# Pads from dummy_pads.lef drawn the way some pad libraries draw theirs.
# With one obstruction over the whole cell on every
# layer the pad draws, with the pins carved out of it.  The pins are
# unchanged.  The fillers draw nothing in dummy_pads.lef; in such a library
# they carry the padring on the same layers and are drawn the same way.
#
# Read it before dummy_pads.lef so these are the definitions used; the
# originals are then ignored as duplicates.
VERSION 5.8 ;

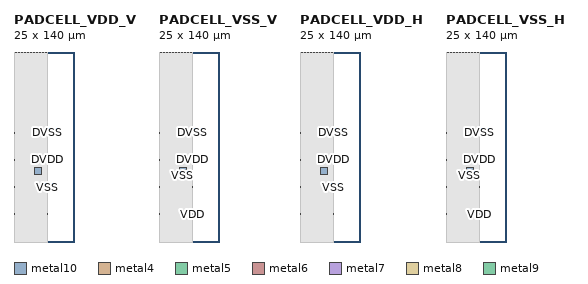
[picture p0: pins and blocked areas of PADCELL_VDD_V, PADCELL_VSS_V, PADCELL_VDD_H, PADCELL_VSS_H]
MACRO PADCELL_VDD_V
  CLASS PAD AREAIO ;
  ORIGIN 0 0 ;
  SIZE 25.0 BY 140 ;
  SYMMETRY X Y R90 ;
  PIN VDD
    DIRECTION INOUT ;
    USE POWER ;
    SHAPE ABUTMENT ;
    PORT
      CLASS BUMP ;
      LAYER metal10 ;
        RECT 15.0 50.0 20.0 55.0 ;
    END
    PORT
      CLASS CORE ;
      LAYER metal4 ;
      RECT 23.155 139.900 23.945 140.000 ;
      LAYER metal4 ;
      RECT 20.995 139.900 21.785 140.000 ;
      LAYER metal4 ;
      RECT 18.835 139.900 19.625 140.000 ;
      LAYER metal4 ;
      RECT 16.565 139.900 17.355 140.000 ;
      LAYER metal4 ;
      RECT 14.295 139.900 15.085 140.000 ;
      LAYER metal4 ;
      RECT 12.135 139.900 12.925 140.000 ;
      LAYER metal4 ;
      RECT 9.975 139.900 10.765 140.000 ;
      LAYER metal4 ;
      RECT 7.815 139.900 8.605 140.000 ;
      LAYER metal4 ;
      RECT 5.655 139.900 6.445 140.000 ;
      LAYER metal4 ;
      RECT 3.495 139.900 4.285 140.000 ;
      LAYER metal4 ;
      RECT 1.335 139.900 2.125 140.000 ;
      LAYER metal5 ;
      RECT 23.155 139.900 23.945 140.000 ;
      LAYER metal5 ;
      RECT 20.995 139.900 21.785 140.000 ;
      LAYER metal5 ;
      RECT 18.835 139.900 19.625 140.000 ;
      LAYER metal5 ;
      RECT 16.565 139.900 17.355 140.000 ;
      LAYER metal5 ;
      RECT 14.295 139.900 15.085 140.000 ;
      LAYER metal5 ;
      RECT 12.135 139.900 12.925 140.000 ;
      LAYER metal5 ;
      RECT 9.975 139.900 10.765 140.000 ;
      LAYER metal5 ;
      RECT 7.815 139.900 8.605 140.000 ;
      LAYER metal5 ;
      RECT 5.655 139.900 6.445 140.000 ;
      LAYER metal5 ;
      RECT 3.495 139.900 4.285 140.000 ;
      LAYER metal5 ;
      RECT 1.335 139.900 2.125 140.000 ;
      LAYER metal6 ;
      RECT 23.155 139.900 23.945 140.000 ;
      LAYER metal6 ;
      RECT 20.995 139.900 21.785 140.000 ;
      LAYER metal6 ;
      RECT 18.835 139.900 19.625 140.000 ;
      LAYER metal6 ;
      RECT 16.565 139.900 17.355 140.000 ;
      LAYER metal6 ;
      RECT 14.295 139.900 15.085 140.000 ;
      LAYER metal6 ;
      RECT 12.135 139.900 12.925 140.000 ;
      LAYER metal6 ;
      RECT 9.975 139.900 10.765 140.000 ;
      LAYER metal6 ;
      RECT 7.815 139.900 8.605 140.000 ;
      LAYER metal6 ;
      RECT 5.655 139.900 6.445 140.000 ;
      LAYER metal6 ;
      RECT 3.495 139.900 4.285 140.000 ;
      LAYER metal6 ;
      RECT 1.335 139.900 2.125 140.000 ;
      LAYER metal7 ;
      RECT 23.155 139.900 23.945 140.000 ;
      LAYER metal7 ;
      RECT 20.995 139.900 21.785 140.000 ;
      LAYER metal7 ;
      RECT 18.835 139.900 19.625 140.000 ;
      LAYER metal7 ;
      RECT 16.565 139.900 17.355 140.000 ;
      LAYER metal7 ;
      RECT 14.295 139.900 15.085 140.000 ;
      LAYER metal7 ;
      RECT 12.135 139.900 12.925 140.000 ;
      LAYER metal7 ;
      RECT 9.975 139.900 10.765 140.000 ;
      LAYER metal7 ;
      RECT 7.815 139.900 8.605 140.000 ;
      LAYER metal7 ;
      RECT 5.655 139.900 6.445 140.000 ;
      LAYER metal7 ;
      RECT 3.495 139.900 4.285 140.000 ;
      LAYER metal7 ;
      RECT 1.335 139.900 2.125 140.000 ;
      LAYER metal8 ;
      RECT 23.155 139.900 23.945 140.000 ;
      LAYER metal8 ;
      RECT 20.995 139.900 21.785 140.000 ;
      LAYER metal8 ;
      RECT 18.835 139.900 19.625 140.000 ;
      LAYER metal8 ;
      RECT 16.565 139.900 17.355 140.000 ;
      LAYER metal8 ;
      RECT 14.295 139.900 15.085 140.000 ;
      LAYER metal8 ;
      RECT 12.135 139.900 12.925 140.000 ;
      LAYER metal8 ;
      RECT 9.975 139.900 10.765 140.000 ;
      LAYER metal8 ;
      RECT 7.815 139.900 8.605 140.000 ;
      LAYER metal8 ;
      RECT 5.655 139.900 6.445 140.000 ;
      LAYER metal8 ;
      RECT 3.495 139.900 4.285 140.000 ;
      LAYER metal8 ;
      RECT 1.335 139.900 2.125 140.000 ;
      LAYER metal9 ;
      RECT 23.155 139.900 23.945 140.000 ;
      LAYER metal9 ;
      RECT 20.995 139.900 21.785 140.000 ;
      LAYER metal9 ;
      RECT 18.835 139.900 19.625 140.000 ;
      LAYER metal9 ;
      RECT 16.565 139.900 17.355 140.000 ;
      LAYER metal9 ;
      RECT 14.295 139.900 15.085 140.000 ;
      LAYER metal9 ;
      RECT 12.135 139.900 12.925 140.000 ;
      LAYER metal9 ;
      RECT 9.975 139.900 10.765 140.000 ;
      LAYER metal9 ;
      RECT 7.815 139.900 8.605 140.000 ;
      LAYER metal9 ;
      RECT 5.655 139.900 6.445 140.000 ;
      LAYER metal9 ;
      RECT 3.495 139.900 4.285 140.000 ;
      LAYER metal9 ;
      RECT 1.335 139.900 2.125 140.000 ;
      LAYER metal4 ;
      RECT 0.000 20.0 0.100 21.0 ;
      LAYER metal4 ;
      RECT 24.90 20.0 25.00 21.0 ;
    END
  END VDD
  PIN VSS
    USE GROUND ;
    PORT
      CLASS CORE ;
      LAYER metal4 ;
      RECT 0.000 40.0 0.100 41.0 ;
      LAYER metal4 ;
      RECT 24.90 40.0 25.00 41.0 ;
    END
  END VSS
  PIN DVDD
    USE POWER ;
    PORT
      CLASS CORE ;
      LAYER metal4 ;
      RECT 0.000 60.0 0.100 61.0 ;
      LAYER metal4 ;
      RECT 24.90 60.0 25.00 61.0 ;
    END
  END DVDD
  PIN DVSS
    USE GROUND ;
    PORT
      CLASS CORE ;
      LAYER metal4 ;
      RECT 0.000 80.0 0.100 81.0 ;
      LAYER metal4 ;
      RECT 24.90 80.0 25.00 81.0 ;
    END
  END DVSS
  OBS
    LAYER metal4 ;
      RECT 0 0 25.0 140 ;
    LAYER metal5 ;
      RECT 0 0 25.0 140 ;
    LAYER metal6 ;
      RECT 0 0 25.0 140 ;
    LAYER metal7 ;
      RECT 0 0 25.0 140 ;
    LAYER metal8 ;
      RECT 0 0 25.0 140 ;
    LAYER metal9 ;
      RECT 0 0 25.0 140 ;
    LAYER metal10 ;
      RECT 0 0 25.0 140 ;
  END
END PADCELL_VDD_V

MACRO PADCELL_VSS_V
  CLASS PAD AREAIO ;
  ORIGIN 0 0 ;
  SIZE 25.0 BY 140 ;
  SYMMETRY X Y R90 ;
  PIN VSS
    DIRECTION INOUT ;
    USE GROUND ;
    SHAPE ABUTMENT ;
    PORT
      CLASS BUMP ;
      LAYER metal10 ;
        RECT 15.0 50.0 20.0 55.0 ;
    END
    PORT
      CLASS CORE ;
      LAYER metal4 ;
      RECT 23.155 139.900 23.945 140.000 ;
      LAYER metal4 ;
      RECT 20.995 139.900 21.785 140.000 ;
      LAYER metal4 ;
      RECT 18.835 139.900 19.625 140.000 ;
      LAYER metal4 ;
      RECT 16.565 139.900 17.355 140.000 ;
      LAYER metal4 ;
      RECT 14.295 139.900 15.085 140.000 ;
      LAYER metal4 ;
      RECT 12.135 139.900 12.925 140.000 ;
      LAYER metal4 ;
      RECT 9.975 139.900 10.765 140.000 ;
      LAYER metal4 ;
      RECT 7.815 139.900 8.605 140.000 ;
      LAYER metal4 ;
      RECT 5.655 139.900 6.445 140.000 ;
      LAYER metal4 ;
      RECT 3.495 139.900 4.285 140.000 ;
      LAYER metal4 ;
      RECT 1.335 139.900 2.125 140.000 ;
      LAYER metal5 ;
      RECT 23.155 139.900 23.945 140.000 ;
      LAYER metal5 ;
      RECT 20.995 139.900 21.785 140.000 ;
      LAYER metal5 ;
      RECT 18.835 139.900 19.625 140.000 ;
      LAYER metal5 ;
      RECT 16.565 139.900 17.355 140.000 ;
      LAYER metal5 ;
      RECT 14.295 139.900 15.085 140.000 ;
      LAYER metal5 ;
      RECT 12.135 139.900 12.925 140.000 ;
      LAYER metal5 ;
      RECT 9.975 139.900 10.765 140.000 ;
      LAYER metal5 ;
      RECT 7.815 139.900 8.605 140.000 ;
      LAYER metal5 ;
      RECT 5.655 139.900 6.445 140.000 ;
      LAYER metal5 ;
      RECT 3.495 139.900 4.285 140.000 ;
      LAYER metal5 ;
      RECT 1.335 139.900 2.125 140.000 ;
      LAYER metal6 ;
      RECT 23.155 139.900 23.945 140.000 ;
      LAYER metal6 ;
      RECT 20.995 139.900 21.785 140.000 ;
      LAYER metal6 ;
      RECT 18.835 139.900 19.625 140.000 ;
      LAYER metal6 ;
      RECT 16.565 139.900 17.355 140.000 ;
      LAYER metal6 ;
      RECT 14.295 139.900 15.085 140.000 ;
      LAYER metal6 ;
      RECT 12.135 139.900 12.925 140.000 ;
      LAYER metal6 ;
      RECT 9.975 139.900 10.765 140.000 ;
      LAYER metal6 ;
      RECT 7.815 139.900 8.605 140.000 ;
      LAYER metal6 ;
      RECT 5.655 139.900 6.445 140.000 ;
      LAYER metal6 ;
      RECT 3.495 139.900 4.285 140.000 ;
      LAYER metal6 ;
      RECT 1.335 139.900 2.125 140.000 ;
      LAYER metal7 ;
      RECT 23.155 139.900 23.945 140.000 ;
      LAYER metal7 ;
      RECT 20.995 139.900 21.785 140.000 ;
      LAYER metal7 ;
      RECT 18.835 139.900 19.625 140.000 ;
      LAYER metal7 ;
      RECT 16.565 139.900 17.355 140.000 ;
      LAYER metal7 ;
      RECT 14.295 139.900 15.085 140.000 ;
      LAYER metal7 ;
      RECT 12.135 139.900 12.925 140.000 ;
      LAYER metal7 ;
      RECT 9.975 139.900 10.765 140.000 ;
      LAYER metal7 ;
      RECT 7.815 139.900 8.605 140.000 ;
      LAYER metal7 ;
      RECT 5.655 139.900 6.445 140.000 ;
      LAYER metal7 ;
      RECT 3.495 139.900 4.285 140.000 ;
      LAYER metal7 ;
      RECT 1.335 139.900 2.125 140.000 ;
      LAYER metal8 ;
      RECT 23.155 139.900 23.945 140.000 ;
      LAYER metal8 ;
      RECT 20.995 139.900 21.785 140.000 ;
      LAYER metal8 ;
      RECT 18.835 139.900 19.625 140.000 ;
      LAYER metal8 ;
      RECT 16.565 139.900 17.355 140.000 ;
      LAYER metal8 ;
      RECT 14.295 139.900 15.085 140.000 ;
      LAYER metal8 ;
      RECT 12.135 139.900 12.925 140.000 ;
      LAYER metal8 ;
      RECT 9.975 139.900 10.765 140.000 ;
      LAYER metal8 ;
      RECT 7.815 139.900 8.605 140.000 ;
      LAYER metal8 ;
      RECT 5.655 139.900 6.445 140.000 ;
      LAYER metal8 ;
      RECT 3.495 139.900 4.285 140.000 ;
      LAYER metal8 ;
      RECT 1.335 139.900 2.125 140.000 ;
      LAYER metal9 ;
      RECT 23.155 139.900 23.945 140.000 ;
      LAYER metal9 ;
      RECT 20.995 139.900 21.785 140.000 ;
      LAYER metal9 ;
      RECT 18.835 139.900 19.625 140.000 ;
      LAYER metal9 ;
      RECT 16.565 139.900 17.355 140.000 ;
      LAYER metal9 ;
      RECT 14.295 139.900 15.085 140.000 ;
      LAYER metal9 ;
      RECT 12.135 139.900 12.925 140.000 ;
      LAYER metal9 ;
      RECT 9.975 139.900 10.765 140.000 ;
      LAYER metal9 ;
      RECT 7.815 139.900 8.605 140.000 ;
      LAYER metal9 ;
      RECT 5.655 139.900 6.445 140.000 ;
      LAYER metal9 ;
      RECT 3.495 139.900 4.285 140.000 ;
      LAYER metal9 ;
      RECT 1.335 139.900 2.125 140.000 ;
      LAYER metal4 ;
      RECT 0.000 40.0 0.100 41.0 ;
      LAYER metal4 ;
      RECT 24.90 40.0 25.00 41.0 ;
    END
  END VSS
  PIN VDD
    USE POWER ;
    PORT
      CLASS CORE ;
      LAYER metal4 ;
      RECT 0.000 20.0 0.100 21.0 ;
      LAYER metal4 ;
      RECT 24.90 20.0 25.00 21.0 ;
    END
  END VDD
  PIN DVDD
    USE POWER ;
    PORT
      CLASS CORE ;
      LAYER metal4 ;
      RECT 0.000 60.0 0.100 61.0 ;
      LAYER metal4 ;
      RECT 24.90 60.0 25.00 61.0 ;
    END
  END DVDD
  PIN DVSS
    USE GROUND ;
    PORT
      CLASS CORE ;
      LAYER metal4 ;
      RECT 0.000 80.0 0.100 81.0 ;
      LAYER metal4 ;
      RECT 24.90 80.0 25.00 81.0 ;
    END
  END DVSS
  OBS
    LAYER metal4 ;
      RECT 0 0 25.0 140 ;
    LAYER metal5 ;
      RECT 0 0 25.0 140 ;
    LAYER metal6 ;
      RECT 0 0 25.0 140 ;
    LAYER metal7 ;
      RECT 0 0 25.0 140 ;
    LAYER metal8 ;
      RECT 0 0 25.0 140 ;
    LAYER metal9 ;
      RECT 0 0 25.0 140 ;
    LAYER metal10 ;
      RECT 0 0 25.0 140 ;
  END
END PADCELL_VSS_V

MACRO PADCELL_VDD_H
  CLASS PAD AREAIO ;
  ORIGIN 0 0 ;
  SIZE 25.0 BY 140 ;
  SYMMETRY X Y R90 ;
  PIN VDD
    DIRECTION INOUT ;
    USE POWER ;
    SHAPE ABUTMENT ;
    PORT
      CLASS BUMP ;
      LAYER metal10 ;
        RECT 15.0 50.0 20.0 55.0 ;
    END
    PORT
      CLASS CORE ;
      LAYER metal4 ;
      RECT 23.155 139.900 23.945 140.000 ;
      LAYER metal4 ;
      RECT 20.995 139.900 21.785 140.000 ;
      LAYER metal4 ;
      RECT 18.835 139.900 19.625 140.000 ;
      LAYER metal4 ;
      RECT 16.565 139.900 17.355 140.000 ;
      LAYER metal4 ;
      RECT 14.295 139.900 15.085 140.000 ;
      LAYER metal4 ;
      RECT 12.135 139.900 12.925 140.000 ;
      LAYER metal4 ;
      RECT 9.975 139.900 10.765 140.000 ;
      LAYER metal4 ;
      RECT 7.815 139.900 8.605 140.000 ;
      LAYER metal4 ;
      RECT 5.655 139.900 6.445 140.000 ;
      LAYER metal4 ;
      RECT 3.495 139.900 4.285 140.000 ;
      LAYER metal4 ;
      RECT 1.335 139.900 2.125 140.000 ;
      LAYER metal5 ;
      RECT 23.155 139.900 23.945 140.000 ;
      LAYER metal5 ;
      RECT 20.995 139.900 21.785 140.000 ;
      LAYER metal5 ;
      RECT 18.835 139.900 19.625 140.000 ;
      LAYER metal5 ;
      RECT 16.565 139.900 17.355 140.000 ;
      LAYER metal5 ;
      RECT 14.295 139.900 15.085 140.000 ;
      LAYER metal5 ;
      RECT 12.135 139.900 12.925 140.000 ;
      LAYER metal5 ;
      RECT 9.975 139.900 10.765 140.000 ;
      LAYER metal5 ;
      RECT 7.815 139.900 8.605 140.000 ;
      LAYER metal5 ;
      RECT 5.655 139.900 6.445 140.000 ;
      LAYER metal5 ;
      RECT 3.495 139.900 4.285 140.000 ;
      LAYER metal5 ;
      RECT 1.335 139.900 2.125 140.000 ;
      LAYER metal6 ;
      RECT 23.155 139.900 23.945 140.000 ;
      LAYER metal6 ;
      RECT 20.995 139.900 21.785 140.000 ;
      LAYER metal6 ;
      RECT 18.835 139.900 19.625 140.000 ;
      LAYER metal6 ;
      RECT 16.565 139.900 17.355 140.000 ;
      LAYER metal6 ;
      RECT 14.295 139.900 15.085 140.000 ;
      LAYER metal6 ;
      RECT 12.135 139.900 12.925 140.000 ;
      LAYER metal6 ;
      RECT 9.975 139.900 10.765 140.000 ;
      LAYER metal6 ;
      RECT 7.815 139.900 8.605 140.000 ;
      LAYER metal6 ;
      RECT 5.655 139.900 6.445 140.000 ;
      LAYER metal6 ;
      RECT 3.495 139.900 4.285 140.000 ;
      LAYER metal6 ;
      RECT 1.335 139.900 2.125 140.000 ;
      LAYER metal7 ;
      RECT 23.155 139.900 23.945 140.000 ;
      LAYER metal7 ;
      RECT 20.995 139.900 21.785 140.000 ;
      LAYER metal7 ;
      RECT 18.835 139.900 19.625 140.000 ;
      LAYER metal7 ;
      RECT 16.565 139.900 17.355 140.000 ;
      LAYER metal7 ;
      RECT 14.295 139.900 15.085 140.000 ;
      LAYER metal7 ;
      RECT 12.135 139.900 12.925 140.000 ;
      LAYER metal7 ;
      RECT 9.975 139.900 10.765 140.000 ;
      LAYER metal7 ;
      RECT 7.815 139.900 8.605 140.000 ;
      LAYER metal7 ;
      RECT 5.655 139.900 6.445 140.000 ;
      LAYER metal7 ;
      RECT 3.495 139.900 4.285 140.000 ;
      LAYER metal7 ;
      RECT 1.335 139.900 2.125 140.000 ;
      LAYER metal8 ;
      RECT 23.155 139.900 23.945 140.000 ;
      LAYER metal8 ;
      RECT 20.995 139.900 21.785 140.000 ;
      LAYER metal8 ;
      RECT 18.835 139.900 19.625 140.000 ;
      LAYER metal8 ;
      RECT 16.565 139.900 17.355 140.000 ;
      LAYER metal8 ;
      RECT 14.295 139.900 15.085 140.000 ;
      LAYER metal8 ;
      RECT 12.135 139.900 12.925 140.000 ;
      LAYER metal8 ;
      RECT 9.975 139.900 10.765 140.000 ;
      LAYER metal8 ;
      RECT 7.815 139.900 8.605 140.000 ;
      LAYER metal8 ;
      RECT 5.655 139.900 6.445 140.000 ;
      LAYER metal8 ;
      RECT 3.495 139.900 4.285 140.000 ;
      LAYER metal8 ;
      RECT 1.335 139.900 2.125 140.000 ;
      LAYER metal9 ;
      RECT 23.155 139.900 23.945 140.000 ;
      LAYER metal9 ;
      RECT 20.995 139.900 21.785 140.000 ;
      LAYER metal9 ;
      RECT 18.835 139.900 19.625 140.000 ;
      LAYER metal9 ;
      RECT 16.565 139.900 17.355 140.000 ;
      LAYER metal9 ;
      RECT 14.295 139.900 15.085 140.000 ;
      LAYER metal9 ;
      RECT 12.135 139.900 12.925 140.000 ;
      LAYER metal9 ;
      RECT 9.975 139.900 10.765 140.000 ;
      LAYER metal9 ;
      RECT 7.815 139.900 8.605 140.000 ;
      LAYER metal9 ;
      RECT 5.655 139.900 6.445 140.000 ;
      LAYER metal9 ;
      RECT 3.495 139.900 4.285 140.000 ;
      LAYER metal9 ;
      RECT 1.335 139.900 2.125 140.000 ;
      LAYER metal4 ;
      RECT 0.000 20.0 0.100 21.0 ;
      LAYER metal4 ;
      RECT 24.90 20.0 25.00 21.0 ;
    END
  END VDD
  PIN VSS
    USE GROUND ;
    PORT
      CLASS CORE ;
      LAYER metal4 ;
      RECT 0.000 40.0 0.100 41.0 ;
      LAYER metal4 ;
      RECT 24.90 40.0 25.00 41.0 ;
    END
  END VSS
  PIN DVDD
    USE POWER ;
    PORT
      CLASS CORE ;
      LAYER metal4 ;
      RECT 0.000 60.0 0.100 61.0 ;
      LAYER metal4 ;
      RECT 24.90 60.0 25.00 61.0 ;
    END
  END DVDD
  PIN DVSS
    USE GROUND ;
    PORT
      CLASS CORE ;
      LAYER metal4 ;
      RECT 0.000 80.0 0.100 81.0 ;
      LAYER metal4 ;
      RECT 24.90 80.0 25.00 81.0 ;
    END
  END DVSS
  OBS
    LAYER metal4 ;
      RECT 0 0 25.0 140 ;
    LAYER metal5 ;
      RECT 0 0 25.0 140 ;
    LAYER metal6 ;
      RECT 0 0 25.0 140 ;
    LAYER metal7 ;
      RECT 0 0 25.0 140 ;
    LAYER metal8 ;
      RECT 0 0 25.0 140 ;
    LAYER metal9 ;
      RECT 0 0 25.0 140 ;
    LAYER metal10 ;
      RECT 0 0 25.0 140 ;
  END
END PADCELL_VDD_H

MACRO PADCELL_VSS_H
  CLASS PAD AREAIO ;
  ORIGIN 0 0 ;
  SIZE 25.0 BY 140 ;
  SYMMETRY X Y R90 ;
  PIN VSS
    DIRECTION INOUT ;
    USE GROUND ;
    SHAPE ABUTMENT ;
    PORT
      CLASS BUMP ;
      LAYER metal10 ;
        RECT 15.0 50.0 20.0 55.0 ;
    END
    PORT
      CLASS CORE ;
      LAYER metal4 ;
      RECT 23.155 139.900 23.945 140.000 ;
      LAYER metal4 ;
      RECT 20.995 139.900 21.785 140.000 ;
      LAYER metal4 ;
      RECT 18.835 139.900 19.625 140.000 ;
      LAYER metal4 ;
      RECT 16.565 139.900 17.355 140.000 ;
      LAYER metal4 ;
      RECT 14.295 139.900 15.085 140.000 ;
      LAYER metal4 ;
      RECT 12.135 139.900 12.925 140.000 ;
      LAYER metal4 ;
      RECT 9.975 139.900 10.765 140.000 ;
      LAYER metal4 ;
      RECT 7.815 139.900 8.605 140.000 ;
      LAYER metal4 ;
      RECT 5.655 139.900 6.445 140.000 ;
      LAYER metal4 ;
      RECT 3.495 139.900 4.285 140.000 ;
      LAYER metal4 ;
      RECT 1.335 139.900 2.125 140.000 ;
      LAYER metal5 ;
      RECT 23.155 139.900 23.945 140.000 ;
      LAYER metal5 ;
      RECT 20.995 139.900 21.785 140.000 ;
      LAYER metal5 ;
      RECT 18.835 139.900 19.625 140.000 ;
      LAYER metal5 ;
      RECT 16.565 139.900 17.355 140.000 ;
      LAYER metal5 ;
      RECT 14.295 139.900 15.085 140.000 ;
      LAYER metal5 ;
      RECT 12.135 139.900 12.925 140.000 ;
      LAYER metal5 ;
      RECT 9.975 139.900 10.765 140.000 ;
      LAYER metal5 ;
      RECT 7.815 139.900 8.605 140.000 ;
      LAYER metal5 ;
      RECT 5.655 139.900 6.445 140.000 ;
      LAYER metal5 ;
      RECT 3.495 139.900 4.285 140.000 ;
      LAYER metal5 ;
      RECT 1.335 139.900 2.125 140.000 ;
      LAYER metal6 ;
      RECT 23.155 139.900 23.945 140.000 ;
      LAYER metal6 ;
      RECT 20.995 139.900 21.785 140.000 ;
      LAYER metal6 ;
      RECT 18.835 139.900 19.625 140.000 ;
      LAYER metal6 ;
      RECT 16.565 139.900 17.355 140.000 ;
      LAYER metal6 ;
      RECT 14.295 139.900 15.085 140.000 ;
      LAYER metal6 ;
      RECT 12.135 139.900 12.925 140.000 ;
      LAYER metal6 ;
      RECT 9.975 139.900 10.765 140.000 ;
      LAYER metal6 ;
      RECT 7.815 139.900 8.605 140.000 ;
      LAYER metal6 ;
      RECT 5.655 139.900 6.445 140.000 ;
      LAYER metal6 ;
      RECT 3.495 139.900 4.285 140.000 ;
      LAYER metal6 ;
      RECT 1.335 139.900 2.125 140.000 ;
      LAYER metal7 ;
      RECT 23.155 139.900 23.945 140.000 ;
      LAYER metal7 ;
      RECT 20.995 139.900 21.785 140.000 ;
      LAYER metal7 ;
      RECT 18.835 139.900 19.625 140.000 ;
      LAYER metal7 ;
      RECT 16.565 139.900 17.355 140.000 ;
      LAYER metal7 ;
      RECT 14.295 139.900 15.085 140.000 ;
      LAYER metal7 ;
      RECT 12.135 139.900 12.925 140.000 ;
      LAYER metal7 ;
      RECT 9.975 139.900 10.765 140.000 ;
      LAYER metal7 ;
      RECT 7.815 139.900 8.605 140.000 ;
      LAYER metal7 ;
      RECT 5.655 139.900 6.445 140.000 ;
      LAYER metal7 ;
      RECT 3.495 139.900 4.285 140.000 ;
      LAYER metal7 ;
      RECT 1.335 139.900 2.125 140.000 ;
      LAYER metal8 ;
      RECT 23.155 139.900 23.945 140.000 ;
      LAYER metal8 ;
      RECT 20.995 139.900 21.785 140.000 ;
      LAYER metal8 ;
      RECT 18.835 139.900 19.625 140.000 ;
      LAYER metal8 ;
      RECT 16.565 139.900 17.355 140.000 ;
      LAYER metal8 ;
      RECT 14.295 139.900 15.085 140.000 ;
      LAYER metal8 ;
      RECT 12.135 139.900 12.925 140.000 ;
      LAYER metal8 ;
      RECT 9.975 139.900 10.765 140.000 ;
      LAYER metal8 ;
      RECT 7.815 139.900 8.605 140.000 ;
      LAYER metal8 ;
      RECT 5.655 139.900 6.445 140.000 ;
      LAYER metal8 ;
      RECT 3.495 139.900 4.285 140.000 ;
      LAYER metal8 ;
      RECT 1.335 139.900 2.125 140.000 ;
      LAYER metal9 ;
      RECT 23.155 139.900 23.945 140.000 ;
      LAYER metal9 ;
      RECT 20.995 139.900 21.785 140.000 ;
      LAYER metal9 ;
      RECT 18.835 139.900 19.625 140.000 ;
      LAYER metal9 ;
      RECT 16.565 139.900 17.355 140.000 ;
      LAYER metal9 ;
      RECT 14.295 139.900 15.085 140.000 ;
      LAYER metal9 ;
      RECT 12.135 139.900 12.925 140.000 ;
      LAYER metal9 ;
      RECT 9.975 139.900 10.765 140.000 ;
      LAYER metal9 ;
      RECT 7.815 139.900 8.605 140.000 ;
      LAYER metal9 ;
      RECT 5.655 139.900 6.445 140.000 ;
      LAYER metal9 ;
      RECT 3.495 139.900 4.285 140.000 ;
      LAYER metal9 ;
      RECT 1.335 139.900 2.125 140.000 ;
      LAYER metal4 ;
      RECT 0.000 40.0 0.100 41.0 ;
      LAYER metal4 ;
      RECT 24.90 40.0 25.00 41.0 ;
    END
  END VSS
  PIN VDD
    USE POWER ;
    PORT
      CLASS CORE ;
      LAYER metal4 ;
      RECT 0.000 20.0 0.100 21.0 ;
      LAYER metal4 ;
      RECT 24.90 20.0 25.00 21.0 ;
    END
  END VDD
  PIN DVDD
    USE POWER ;
    PORT
      CLASS CORE ;
      LAYER metal4 ;
      RECT 0.000 60.0 0.100 61.0 ;
      LAYER metal4 ;
      RECT 24.90 60.0 25.00 61.0 ;
    END
  END DVDD
  PIN DVSS
    USE GROUND ;
    PORT
      CLASS CORE ;
      LAYER metal4 ;
      RECT 0.000 80.0 0.100 81.0 ;
      LAYER metal4 ;
      RECT 24.90 80.0 25.00 81.0 ;
    END
  END DVSS
  OBS
    LAYER metal4 ;
      RECT 0 0 25.0 140 ;
    LAYER metal5 ;
      RECT 0 0 25.0 140 ;
    LAYER metal6 ;
      RECT 0 0 25.0 140 ;
    LAYER metal7 ;
      RECT 0 0 25.0 140 ;
    LAYER metal8 ;
      RECT 0 0 25.0 140 ;
    LAYER metal9 ;
      RECT 0 0 25.0 140 ;
    LAYER metal10 ;
      RECT 0 0 25.0 140 ;
  END
END PADCELL_VSS_H

MACRO PAD_FILL1_V
  CLASS PAD SPACER ;
  ORIGIN 0 0 ;
  SIZE 1 BY 140 ;
  SYMMETRY X Y R90 ;
  OBS
    LAYER metal4 ;
      RECT 0 0 1 140 ;
    LAYER metal5 ;
      RECT 0 0 1 140 ;
    LAYER metal6 ;
      RECT 0 0 1 140 ;
    LAYER metal7 ;
      RECT 0 0 1 140 ;
    LAYER metal8 ;
      RECT 0 0 1 140 ;
    LAYER metal9 ;
      RECT 0 0 1 140 ;
    LAYER metal10 ;
      RECT 0 0 1 140 ;
  END
END PAD_FILL1_V

MACRO PAD_FILL5_V
  CLASS PAD SPACER ;
  ORIGIN 0 0 ;
  SIZE 5 BY 140 ;
  SYMMETRY X Y R90 ;
  OBS
    LAYER metal4 ;
      RECT 0 0 5 140 ;
    LAYER metal5 ;
      RECT 0 0 5 140 ;
    LAYER metal6 ;
      RECT 0 0 5 140 ;
    LAYER metal7 ;
      RECT 0 0 5 140 ;
    LAYER metal8 ;
      RECT 0 0 5 140 ;
    LAYER metal9 ;
      RECT 0 0 5 140 ;
    LAYER metal10 ;
      RECT 0 0 5 140 ;
  END
END PAD_FILL5_V

MACRO PAD_FILL1_H
  CLASS PAD SPACER ;
  ORIGIN 0 0 ;
  SIZE 140 BY 1 ;
  SYMMETRY X Y R90 ;
  OBS
    LAYER metal4 ;
      RECT 0 0 140 1 ;
    LAYER metal5 ;
      RECT 0 0 140 1 ;
    LAYER metal6 ;
      RECT 0 0 140 1 ;
    LAYER metal7 ;
      RECT 0 0 140 1 ;
    LAYER metal8 ;
      RECT 0 0 140 1 ;
    LAYER metal9 ;
      RECT 0 0 140 1 ;
    LAYER metal10 ;
      RECT 0 0 140 1 ;
  END
END PAD_FILL1_H

MACRO PAD_FILL5_H
  CLASS PAD SPACER ;
  ORIGIN 0 0 ;
  SIZE 140 BY 5 ;
  SYMMETRY X Y R90 ;
  OBS
    LAYER metal4 ;
      RECT 0 0 140 5 ;
    LAYER metal5 ;
      RECT 0 0 140 5 ;
    LAYER metal6 ;
      RECT 0 0 140 5 ;
    LAYER metal7 ;
      RECT 0 0 140 5 ;
    LAYER metal8 ;
      RECT 0 0 140 5 ;
    LAYER metal9 ;
      RECT 0 0 140 5 ;
    LAYER metal10 ;
      RECT 0 0 140 5 ;
  END
END PAD_FILL5_H

END LIBRARY
